One B-rep face of a CAD part: STEP entity #392.
In plain terms, the planar face has unit normal (-1, 0, 0).
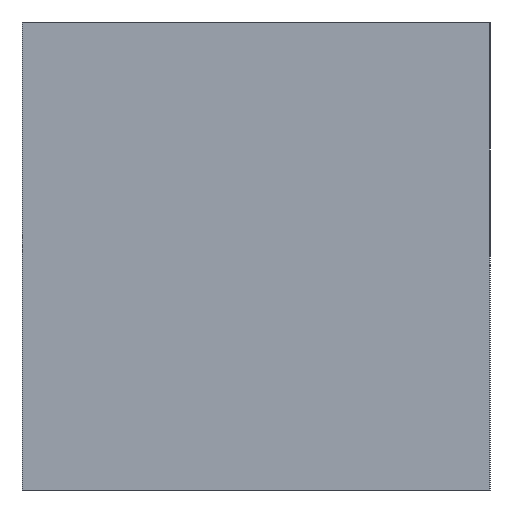
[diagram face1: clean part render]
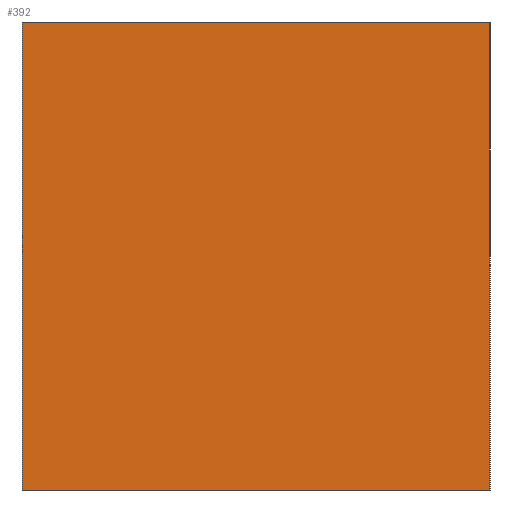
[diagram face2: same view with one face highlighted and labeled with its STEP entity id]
Its self-contained STEP definition (entity closure, numbers rounded to 3 decimals):
#392 = ADVANCED_FACE('',(#393),#407,.F.);
#393 = FACE_BOUND('',#394,.F.);
#394 = EDGE_LOOP('',(#395,#430,#458,#486));
#395 = ORIENTED_EDGE('',*,*,#396,.F.);
#396 = EDGE_CURVE('',#397,#399,#401,.T.);
#397 = VERTEX_POINT('',#398);
#398 = CARTESIAN_POINT('',(-3.05,-1.345,0.));
#399 = VERTEX_POINT('',#400);
#400 = CARTESIAN_POINT('',(-3.05,-1.345,2.69));
#401 = SURFACE_CURVE('',#402,(#406,#418),.PCURVE_S1.);
#402 = LINE('',#403,#404);
#403 = CARTESIAN_POINT('',(-3.05,-1.345,0.));
#404 = VECTOR('',#405,1.);
#405 = DIRECTION('',(0.,0.,1.));
#406 = PCURVE('',#407,#412);
#407 = PLANE('',#408);
#408 = AXIS2_PLACEMENT_3D('',#409,#410,#411);
#409 = CARTESIAN_POINT('',(-3.05,-1.345,0.));
#410 = DIRECTION('',(1.,0.,0.));
#411 = DIRECTION('',(0.,0.,1.));
#412 = DEFINITIONAL_REPRESENTATION('',(#413),#417);
#413 = LINE('',#414,#415);
#414 = CARTESIAN_POINT('',(0.,0.));
#415 = VECTOR('',#416,1.);
#416 = DIRECTION('',(1.,0.));
#417 = ( GEOMETRIC_REPRESENTATION_CONTEXT(2) 
PARAMETRIC_REPRESENTATION_CONTEXT() REPRESENTATION_CONTEXT('2D SPACE',''
  ) );
#418 = PCURVE('',#419,#424);
#419 = PLANE('',#420);
#420 = AXIS2_PLACEMENT_3D('',#421,#422,#423);
#421 = CARTESIAN_POINT('',(-3.05,-1.345,0.));
#422 = DIRECTION('',(0.,1.,0.));
#423 = DIRECTION('',(0.,0.,1.));
#424 = DEFINITIONAL_REPRESENTATION('',(#425),#429);
#425 = LINE('',#426,#427);
#426 = CARTESIAN_POINT('',(0.,0.));
#427 = VECTOR('',#428,1.);
#428 = DIRECTION('',(1.,0.));
#429 = ( GEOMETRIC_REPRESENTATION_CONTEXT(2) 
PARAMETRIC_REPRESENTATION_CONTEXT() REPRESENTATION_CONTEXT('2D SPACE',''
  ) );
#430 = ORIENTED_EDGE('',*,*,#431,.T.);
#431 = EDGE_CURVE('',#397,#432,#434,.T.);
#432 = VERTEX_POINT('',#433);
#433 = CARTESIAN_POINT('',(-3.05,1.345,0.));
#434 = SURFACE_CURVE('',#435,(#439,#446),.PCURVE_S1.);
#435 = LINE('',#436,#437);
#436 = CARTESIAN_POINT('',(-3.05,-1.345,0.));
#437 = VECTOR('',#438,1.);
#438 = DIRECTION('',(0.,1.,0.));
#439 = PCURVE('',#407,#440);
#440 = DEFINITIONAL_REPRESENTATION('',(#441),#445);
#441 = LINE('',#442,#443);
#442 = CARTESIAN_POINT('',(0.,0.));
#443 = VECTOR('',#444,1.);
#444 = DIRECTION('',(0.,-1.));
#445 = ( GEOMETRIC_REPRESENTATION_CONTEXT(2) 
PARAMETRIC_REPRESENTATION_CONTEXT() REPRESENTATION_CONTEXT('2D SPACE',''
  ) );
#446 = PCURVE('',#447,#452);
#447 = PLANE('',#448);
#448 = AXIS2_PLACEMENT_3D('',#449,#450,#451);
#449 = CARTESIAN_POINT('',(-3.05,-1.345,0.));
#450 = DIRECTION('',(0.,0.,1.));
#451 = DIRECTION('',(1.,0.,0.));
#452 = DEFINITIONAL_REPRESENTATION('',(#453),#457);
#453 = LINE('',#454,#455);
#454 = CARTESIAN_POINT('',(0.,0.));
#455 = VECTOR('',#456,1.);
#456 = DIRECTION('',(0.,1.));
#457 = ( GEOMETRIC_REPRESENTATION_CONTEXT(2) 
PARAMETRIC_REPRESENTATION_CONTEXT() REPRESENTATION_CONTEXT('2D SPACE',''
  ) );
#458 = ORIENTED_EDGE('',*,*,#459,.T.);
#459 = EDGE_CURVE('',#432,#460,#462,.T.);
#460 = VERTEX_POINT('',#461);
#461 = CARTESIAN_POINT('',(-3.05,1.345,2.69));
#462 = SURFACE_CURVE('',#463,(#467,#474),.PCURVE_S1.);
#463 = LINE('',#464,#465);
#464 = CARTESIAN_POINT('',(-3.05,1.345,0.));
#465 = VECTOR('',#466,1.);
#466 = DIRECTION('',(0.,0.,1.));
#467 = PCURVE('',#407,#468);
#468 = DEFINITIONAL_REPRESENTATION('',(#469),#473);
#469 = LINE('',#470,#471);
#470 = CARTESIAN_POINT('',(0.,-2.69));
#471 = VECTOR('',#472,1.);
#472 = DIRECTION('',(1.,0.));
#473 = ( GEOMETRIC_REPRESENTATION_CONTEXT(2) 
PARAMETRIC_REPRESENTATION_CONTEXT() REPRESENTATION_CONTEXT('2D SPACE',''
  ) );
#474 = PCURVE('',#475,#480);
#475 = PLANE('',#476);
#476 = AXIS2_PLACEMENT_3D('',#477,#478,#479);
#477 = CARTESIAN_POINT('',(-3.05,1.345,0.));
#478 = DIRECTION('',(0.,1.,0.));
#479 = DIRECTION('',(0.,0.,1.));
#480 = DEFINITIONAL_REPRESENTATION('',(#481),#485);
#481 = LINE('',#482,#483);
#482 = CARTESIAN_POINT('',(0.,0.));
#483 = VECTOR('',#484,1.);
#484 = DIRECTION('',(1.,0.));
#485 = ( GEOMETRIC_REPRESENTATION_CONTEXT(2) 
PARAMETRIC_REPRESENTATION_CONTEXT() REPRESENTATION_CONTEXT('2D SPACE',''
  ) );
#486 = ORIENTED_EDGE('',*,*,#487,.F.);
#487 = EDGE_CURVE('',#399,#460,#488,.T.);
#488 = SURFACE_CURVE('',#489,(#493,#500),.PCURVE_S1.);
#489 = LINE('',#490,#491);
#490 = CARTESIAN_POINT('',(-3.05,-1.345,2.69));
#491 = VECTOR('',#492,1.);
#492 = DIRECTION('',(0.,1.,0.));
#493 = PCURVE('',#407,#494);
#494 = DEFINITIONAL_REPRESENTATION('',(#495),#499);
#495 = LINE('',#496,#497);
#496 = CARTESIAN_POINT('',(2.69,0.));
#497 = VECTOR('',#498,1.);
#498 = DIRECTION('',(0.,-1.));
#499 = ( GEOMETRIC_REPRESENTATION_CONTEXT(2) 
PARAMETRIC_REPRESENTATION_CONTEXT() REPRESENTATION_CONTEXT('2D SPACE',''
  ) );
#500 = PCURVE('',#501,#506);
#501 = PLANE('',#502);
#502 = AXIS2_PLACEMENT_3D('',#503,#504,#505);
#503 = CARTESIAN_POINT('',(-3.05,-1.345,2.69));
#504 = DIRECTION('',(0.,0.,1.));
#505 = DIRECTION('',(1.,0.,0.));
#506 = DEFINITIONAL_REPRESENTATION('',(#507),#511);
#507 = LINE('',#508,#509);
#508 = CARTESIAN_POINT('',(0.,0.));
#509 = VECTOR('',#510,1.);
#510 = DIRECTION('',(0.,1.));
#511 = ( GEOMETRIC_REPRESENTATION_CONTEXT(2) 
PARAMETRIC_REPRESENTATION_CONTEXT() REPRESENTATION_CONTEXT('2D SPACE',''
  ) );
